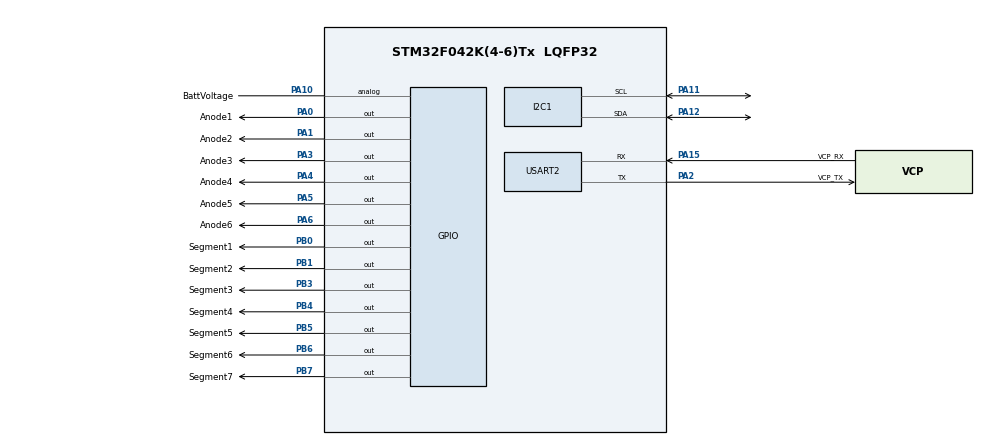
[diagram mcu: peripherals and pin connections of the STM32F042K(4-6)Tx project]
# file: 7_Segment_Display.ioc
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Mcu.Family=STM32F0
PA14.GPIO_Label=SWCLK
PA0.GPIO_Label=Anode1
PA11.Mode=I2C
PA6.GPIO_Label=Anode6
PB0.GPIO_Label=Segment1
PB6.GPIO_Label=Segment6
ProjectManager.StackSize=0x400
PA13.Signal=SYS_SWDIO
PA15.GPIO_Label=VCP_RX
PA12.Signal=I2C1_SDA
ProjectManager.TargetToolchain=STM32CubeIDE
PB6.Signal=GPIO_Output
PA1.Signal=GPIO_Output
PF0-OSC_IN.Mode=HSE-External-Clock-Source
PA5.Signal=GPIO_Output
PF0-OSC_IN.GPIO_Label=MCO
board=NUCLEO-F042K6
USART2.VirtualMode-Asynchronous=VM_ASYNC
PA15.Mode=Asynchronous
PB4.GPIO_Label=Segment4
PA14.Mode=Serial_Wire
PB1.GPIO_Label=Segment2
PA1.GPIO_Label=Anode2
PA10.GPIO_Label=BattVoltage
PB7.Signal=GPIO_Output
PA13.Mode=Serial_Wire
Mcu.Name=STM32F042K(4-6)Tx
PA2.Signal=USART2_TX
PA13.GPIO_Label=SWDIO
PA0.Signal=GPIO_Output
PB7.GPIO_Label=Segment7
PB3.Signal=GPIO_Output
PA4.Signal=GPIO_Output
Mcu.Package=LQFP32
PB5.Signal=GPIO_Output
PA6.Signal=GPIO_Output
PB1.Signal=GPIO_Output
PA12.Mode=I2C
PA5.GPIO_Label=Anode5
PA2.GPIO_Label=VCP_TX
PA11.Signal=I2C1_SCL
PA10.Signal=GPIO_Analog
PA14.Signal=SYS_SWCLK
PA15.Signal=USART2_RX
ProjectManager.HeapSize=0x200
PB5.GPIO_Label=Segment5
PA2.Mode=Asynchronous
PF0-OSC_IN.Signal=RCC_OSC_IN
PB0.Signal=GPIO_Output
PA4.GPIO_Label=Anode4
PB4.Signal=GPIO_Output
PA3.GPIO_Label=Anode3
PA3.Signal=GPIO_Output
PB3.GPIO_Label=Segment3

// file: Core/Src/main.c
/* USER CODE BEGIN Header */
/**
  ******************************************************************************
  * @file           : main.c
  * @brief          : Main program body
  ******************************************************************************
  * @attention
  *
  * <h2><center>&copy; Copyright (c) 2021 STMicroelectronics.
  * All rights reserved.</center></h2>
  *
  * This software component is licensed by ST under BSD 3-Clause license,
  * the "License"; You may not use this file except in compliance with the
  * License. You may obtain a copy of the License at:
  *                        opensource.org/licenses/BSD-3-Clause
  *
  ******************************************************************************
  */
/* USER CODE END Header */
#include "main.h"
#include "primaryFunctions.h"
#include "DS3231.h"

I2C_HandleTypeDef hi2c1;

UART_HandleTypeDef huart2;

/* USER CODE BEGIN PV */
uint8_t value;
uint8_t value2;
uint8_t commandValue;
char returnMessage[50];

// Variables used for time-keeping
uint8_t hours;
uint8_t minutes;
uint8_t seconds;

uint8_t month;
uint8_t day;
uint8_t year;

uint8_t monthDifference;
uint8_t dayDifference;
uint8_t yearDifference;

GPIO_PinState daylightSavingsTime;
GPIO_PinState displayMode;
/* USER CODE END PV */

void SystemClock_Config(void);
static void MX_GPIO_Init(void);
static void MX_USART2_UART_Init(void);
static void MX_I2C1_Init(void);
/* USER CODE BEGIN PFP */
void displayCurrentTime(void);
void displayDifference(void);
void checkInputs(void);
/* USER CODE END PFP */

int main(void)
{

  /* MCU Configuration--------------------------------------------------------*/

  /* Reset of all peripherals, Initializes the Flash interface and the Systick. */
  HAL_Init();

  /* Configure the system clock */
  SystemClock_Config();

  /* Initialize all configured peripherals */
  MX_GPIO_Init();
  MX_USART2_UART_Init();
  MX_I2C1_Init();

  /* Infinite loop */
  /* USER CODE BEGIN WHILE */
  while (1)
  {
	  // Read the current time
	  hours = readHours(hi2c1);
	  if(daylightSavingsTime == GPIO_PIN_SET)
	  {
		  hours = hours + 1;
	  }
	  minutes = readMinutes(hi2c1);
	  seconds = readSeconds(hi2c1);
	  month = readMonth(hi2c1);
	  day = readDay(hi2c1);
	  year = readYear(hi2c1);

	  // Calculate the difference
	  dayDifference = calculateDayDifference(month, day);
	  monthDifference = calculateMonthDifference(month, day);
	  yearDifference = calculateYearDifference(year, month, day);

	  // Display the time
	  if(displayMode == GPIO_PIN_SET)
	  {
		  displayDifference();
	  }
	  else
	  {
		  displayCurrentTime();
	  }

	  checkInputs();
  }
  /* USER CODE END 3 */
}

void displayCurrentTime(void)
{
  // Turn off all digits while switching cathodes
  displayOff();

  if(hours > 9)
  {
    uint8_t temp;

    digitOne();
    if(hours > 19)
    {
      displayTwo();
      temp = hours - 20;
    }
    else
    {
      displayOne();
      temp = hours - 10;
    }
    HAL_Delay(1);
    displayOff();
    digitTwo();
    displayValue(temp);
    HAL_Delay(1);
    displayOff();
  }
  else
  {
    digitTwo();
    displayValue(hours);
    HAL_Delay(1);
    displayOff();
  }

  uint8_t tensValue;
  tensValue = minutes / 10;
  digitThree();
  displayValue(tensValue);
  HAL_Delay(1);
  displayOff();
  digitFour();

  displayValue(minutes - (tensValue * 10));

  HAL_Delay(1);
  displayOff();

  tensValue = seconds / 10;
  digitFive();
  displayValue(tensValue);
  HAL_Delay(1);
  displayOff();

  digitSix();
  displayValue(seconds - (tensValue * 10));
  HAL_Delay(1);
  displayOff();
}

void displayDifference(void)
{
  // Turn off all digits while switching cathodes
  displayOff();

  uint8_t tensValue;

  if(yearDifference > 9)
  {
    tensValue = yearDifference / 10;
    digitOne();
    displayValue(tensValue);
    HAL_Delay(1);
    displayOff();

    digitTwo();
    displayValue(yearDifference - (tensValue * 10));
    HAL_Delay(1);
    displayOff();
  }
  else
  {
    digitTwo();
    displayValue(yearDifference);
    HAL_Delay(1);
    displayOff();
  }

  if(monthDifference > 9)
  {
    tensValue = monthDifference / 10;
    digitThree();
    displayValue(tensValue);
    HAL_Delay(1);
    displayOff();

    digitFour();
    displayValue(monthDifference - (tensValue * 10));
    HAL_Delay(1);
    displayOff();
  }
  else
  {
    digitFour();
    displayValue(monthDifference);
    HAL_Delay(1);
    displayOff();
  }

  if(dayDifference > 9)
  {
    tensValue = dayDifference / 10;
    digitFive();
    displayValue(tensValue);
    HAL_Delay(1);
    displayOff();

    digitSix();
    displayValue(dayDifference - (tensValue * 10));
    HAL_Delay(1);
    displayOff();
  }
  else
  {
    digitSix();
    displayValue(dayDifference);
    HAL_Delay(1);
    displayOff();
  }
}

void checkInputs(void)
{

	// Check the switches
	daylightSavingsTime = HAL_GPIO_ReadPin(GPIOA, GPIO_PIN_8);
	displayMode = HAL_GPIO_ReadPin(GPIOA, GPIO_PIN_9);
	// Clear out any previous commands
	  commandValue = 0;

  // Determine if any new commands have been sent
  HAL_UART_Receive(&huart2, &commandValue, 1, 0);
  switch(commandValue)
  {
    case 'h':
      HAL_UART_Transmit(&huart2, (uint8_t*)returnMessage, sprintf(returnMessage, "\r\nSet the clock - hours:\r\n"), 500);
      HAL_UART_Receive(&huart2, &value, 1, 10000);
      sendUARTByte(huart2, value-48);
      HAL_UART_Receive(&huart2, &value2, 1, 10000);
      sendUARTByte(huart2, value2-48);
      writeHours(hi2c1, (value-48), (value2-48));
      break;
    case 'm':
      HAL_UART_Transmit(&huart2, (uint8_t*)returnMessage, sprintf(returnMessage, "\r\nSet the clock - minutes:\r\n"), 500);
      HAL_UART_Receive(&huart2, &value, 1, 10000);
      sendUARTByte(huart2, value-48);
      HAL_UART_Receive(&huart2, &value2, 1, 10000);
      sendUARTByte(huart2, value2-48);
      writeMinutes(hi2c1, (value-48), (value2-48));
      break;
    case 's':
      HAL_UART_Transmit(&huart2, (uint8_t*)returnMessage, sprintf(returnMessage, "\r\nSet the clock - seconds:\r\n"), 500);
      HAL_UART_Receive(&huart2, &value, 1, 10000);
      sendUARTByte(huart2, value-48);
      HAL_UART_Receive(&huart2, &value2, 1, 10000);
      sendUARTByte(huart2, value2-48);
      writeSeconds(hi2c1, (value - 48), (value2 - 48));
      break;
    case 'n':
      HAL_UART_Transmit(&huart2, (uint8_t*)returnMessage, sprintf(returnMessage, "\r\nSet the clock - month:\r\n"), 500);
      HAL_UART_Receive(&huart2, &value, 1, 10000);
      sendUARTByte(huart2, value-48);
      HAL_UART_Receive(&huart2, &value2, 1, 10000);
      sendUARTByte(huart2, value2-48);
      writeMonth(hi2c1, (value - 48), (value2 - 48));
      break;
    case 'd':
      HAL_UART_Transmit(&huart2, (uint8_t*)returnMessage, sprintf(returnMessage, "\r\nSet the clock - day:\r\n"), 500);
      HAL_UART_Receive(&huart2, &value, 1, 10000);
      sendUARTByte(huart2, value-48);
      HAL_UART_Receive(&huart2, &value2, 1, 10000);
      sendUARTByte(huart2, value2-48);
      writeDay(hi2c1, (value - 48), (value2 - 48));
      break;
    case 'y':
      HAL_UART_Transmit(&huart2, (uint8_t*)returnMessage, sprintf(returnMessage, "\r\nSet the clock - year:\r\n"), 500);
      HAL_UART_Receive(&huart2, &value, 1, 10000);
      sendUARTByte(huart2, value-48);
      HAL_UART_Receive(&huart2, &value2, 1, 10000);
      sendUARTByte(huart2, value2-48);
      writeYear(hi2c1, (value - 48), (value2 - 48));
      break;
    case 'r':
      HAL_UART_Transmit(&huart2, (uint8_t*)UARTBuffer, sprintf(UARTBuffer, "\r\nCurrent Time: %02d:%02d:%02d", hours, minutes, seconds), 500);
      HAL_UART_Transmit(&huart2, (uint8_t*)UARTBuffer, sprintf(UARTBuffer, "\r\nCurrent Date: %02d/%02d/%02d", month, day, year), 500);
      break;
    case 'M':
      HAL_UART_Transmit(&huart2, (uint8_t*)UARTBuffer, sprintf(UARTBuffer, "\r\nYear Difference: %d", yearDifference), 500);
      HAL_UART_Transmit(&huart2, (uint8_t*)UARTBuffer, sprintf(UARTBuffer, "\r\nMonth Difference: %d", monthDifference), 500);
      HAL_UART_Transmit(&huart2, (uint8_t*)UARTBuffer, sprintf(UARTBuffer, "\r\nDay Difference: %d", dayDifference), 500);
      break;
    default:
      break;
  }
}

void SystemClock_Config(void)
{
  RCC_OscInitTypeDef RCC_OscInitStruct = {0};
  RCC_ClkInitTypeDef RCC_ClkInitStruct = {0};
  RCC_PeriphCLKInitTypeDef PeriphClkInit = {0};

  /** Initializes the RCC Oscillators according to the specified parameters
  * in the RCC_OscInitTypeDef structure.
  */
  RCC_OscInitStruct.OscillatorType = RCC_OSCILLATORTYPE_HSI;
  RCC_OscInitStruct.HSIState = RCC_HSI_ON;
  RCC_OscInitStruct.HSICalibrationValue = RCC_HSICALIBRATION_DEFAULT;
  RCC_OscInitStruct.PLL.PLLState = RCC_PLL_NONE;
  if (HAL_RCC_OscConfig(&RCC_OscInitStruct) != HAL_OK)
  {
    Error_Handler();
  }
  /** Initializes the CPU, AHB and APB buses clocks
  */
  RCC_ClkInitStruct.ClockType = RCC_CLOCKTYPE_HCLK|RCC_CLOCKTYPE_SYSCLK
                              |RCC_CLOCKTYPE_PCLK1;
  RCC_ClkInitStruct.SYSCLKSource = RCC_SYSCLKSOURCE_HSI;
  RCC_ClkInitStruct.AHBCLKDivider = RCC_SYSCLK_DIV1;
  RCC_ClkInitStruct.APB1CLKDivider = RCC_HCLK_DIV1;

  if (HAL_RCC_ClockConfig(&RCC_ClkInitStruct, FLASH_LATENCY_0) != HAL_OK)
  {
    Error_Handler();
  }
  PeriphClkInit.PeriphClockSelection = RCC_PERIPHCLK_I2C1;
  PeriphClkInit.I2c1ClockSelection = RCC_I2C1CLKSOURCE_HSI;
  if (HAL_RCCEx_PeriphCLKConfig(&PeriphClkInit) != HAL_OK)
  {
    Error_Handler();
  }
}

static void MX_I2C1_Init(void)
{

  hi2c1.Instance = I2C1;
  hi2c1.Init.Timing = 0x2000090E;
  hi2c1.Init.OwnAddress1 = 0;
  hi2c1.Init.AddressingMode = I2C_ADDRESSINGMODE_7BIT;
  hi2c1.Init.DualAddressMode = I2C_DUALADDRESS_DISABLE;
  hi2c1.Init.OwnAddress2 = 0;
  hi2c1.Init.OwnAddress2Masks = I2C_OA2_NOMASK;
  hi2c1.Init.GeneralCallMode = I2C_GENERALCALL_DISABLE;
  hi2c1.Init.NoStretchMode = I2C_NOSTRETCH_DISABLE;
  if (HAL_I2C_Init(&hi2c1) != HAL_OK)
  {
    Error_Handler();
  }
  /** Configure Analogue filter
  */
  if (HAL_I2CEx_ConfigAnalogFilter(&hi2c1, I2C_ANALOGFILTER_ENABLE) != HAL_OK)
  {
    Error_Handler();
  }
  /** Configure Digital filter
  */
  if (HAL_I2CEx_ConfigDigitalFilter(&hi2c1, 0) != HAL_OK)
  {
    Error_Handler();
  }

}

static void MX_USART2_UART_Init(void)
{

  huart2.Instance = USART2;
  huart2.Init.BaudRate = 38400;
  huart2.Init.WordLength = UART_WORDLENGTH_8B;
  huart2.Init.StopBits = UART_STOPBITS_1;
  huart2.Init.Parity = UART_PARITY_NONE;
  huart2.Init.Mode = UART_MODE_TX_RX;
  huart2.Init.HwFlowCtl = UART_HWCONTROL_NONE;
  huart2.Init.OverSampling = UART_OVERSAMPLING_16;
  huart2.Init.OneBitSampling = UART_ONE_BIT_SAMPLE_DISABLE;
  huart2.AdvancedInit.AdvFeatureInit = UART_ADVFEATURE_NO_INIT;
  if (HAL_UART_Init(&huart2) != HAL_OK)
  {
    Error_Handler();
  }

}

static void MX_GPIO_Init(void)
{
  GPIO_InitTypeDef GPIO_InitStruct = {0};

  /* GPIO Ports Clock Enable */
  __HAL_RCC_GPIOF_CLK_ENABLE();
  __HAL_RCC_GPIOA_CLK_ENABLE();
  __HAL_RCC_GPIOB_CLK_ENABLE();

  /*Configure GPIO pin Output Level */
  HAL_GPIO_WritePin(GPIOA, Anode1_Pin|Anode2_Pin|Anode3_Pin|Anode4_Pin
                          |Anode5_Pin|Anode6_Pin, GPIO_PIN_RESET);

  /*Configure GPIO pin Output Level */
  HAL_GPIO_WritePin(GPIOB, Segment1_Pin|Segment2_Pin|Segment3_Pin|Segment4_Pin
                          |Segment5_Pin|Segment6_Pin|Segment7_Pin, GPIO_PIN_RESET);

  /*Configure GPIO pins : Anode1_Pin Anode2_Pin Anode3_Pin Anode4_Pin
                           Anode5_Pin Anode6_Pin */
  GPIO_InitStruct.Pin = Anode1_Pin|Anode2_Pin|Anode3_Pin|Anode4_Pin
                          |Anode5_Pin|Anode6_Pin;
  GPIO_InitStruct.Mode = GPIO_MODE_OUTPUT_PP;
  GPIO_InitStruct.Pull = GPIO_NOPULL;
  GPIO_InitStruct.Speed = GPIO_SPEED_FREQ_LOW;
  HAL_GPIO_Init(GPIOA, &GPIO_InitStruct);

  /*Configure GPIO pins : Segment1_Pin Segment2_Pin Segment3_Pin Segment4_Pin
                           Segment5_Pin Segment6_Pin Segment7_Pin */
  GPIO_InitStruct.Pin = Segment1_Pin|Segment2_Pin|Segment3_Pin|Segment4_Pin
                          |Segment5_Pin|Segment6_Pin|Segment7_Pin;
  GPIO_InitStruct.Mode = GPIO_MODE_OUTPUT_PP;
  GPIO_InitStruct.Pull = GPIO_NOPULL;
  GPIO_InitStruct.Speed = GPIO_SPEED_FREQ_LOW;
  HAL_GPIO_Init(GPIOB, &GPIO_InitStruct);

  /*Configure GPIO pin : BattVoltage_Pin */
  GPIO_InitStruct.Pin = BattVoltage_Pin;
  GPIO_InitStruct.Mode = GPIO_MODE_ANALOG;
  GPIO_InitStruct.Pull = GPIO_NOPULL;
  HAL_GPIO_Init(BattVoltage_GPIO_Port, &GPIO_InitStruct);

  /*Configure GPIO pins : PA8 PA9 */
  GPIO_InitStruct.Pin = GPIO_PIN_8|GPIO_PIN_9;
  GPIO_InitStruct.Mode = GPIO_MODE_INPUT;
  GPIO_InitStruct.Pull = GPIO_PULLUP;
  HAL_GPIO_Init(GPIOA, &GPIO_InitStruct);
}

void Error_Handler(void)
{
  __disable_irq();
  while (1)
  {
  }
}

/************************ (C) COPYRIGHT STMicroelectronics *****END OF FILE****/
